VERSION 5.7 ;
  NOWIREEXTENSIONATPIN ON ;
  DIVIDERCHAR "/" ;
  BUSBITCHARS "[]" ;
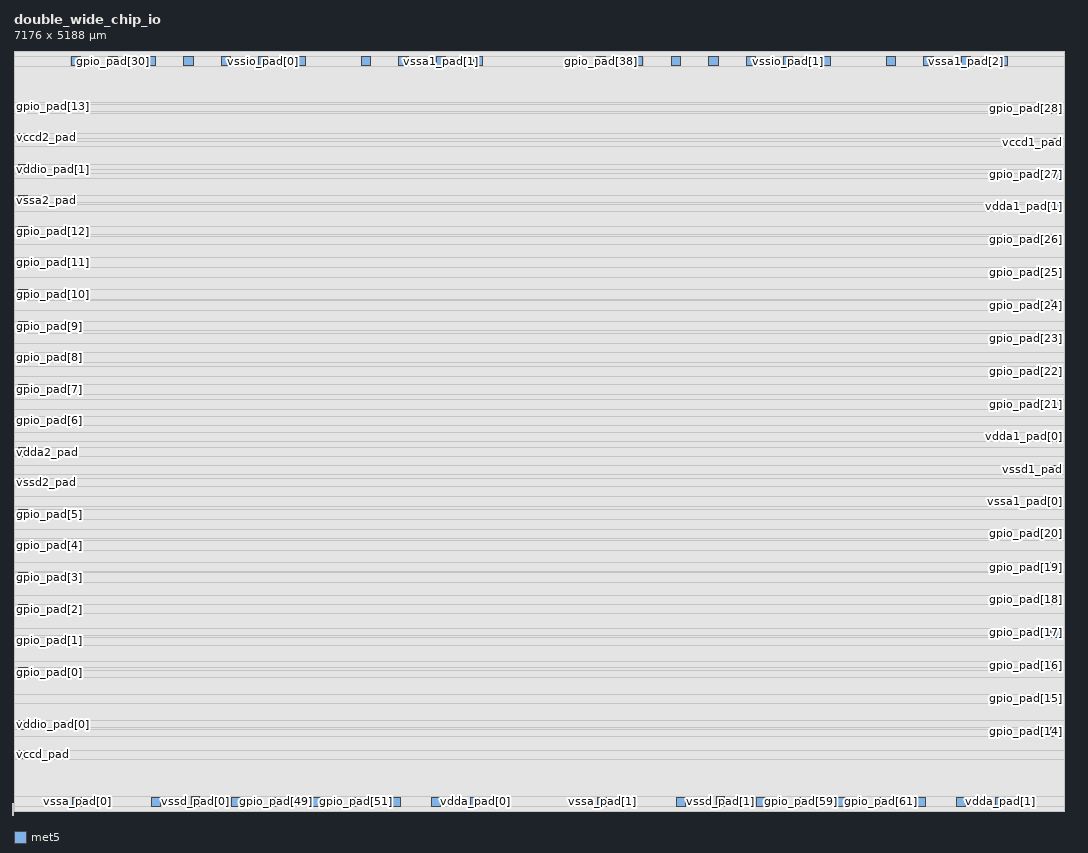
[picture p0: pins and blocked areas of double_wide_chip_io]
MACRO double_wide_chip_io
  CLASS BLOCK ;
  FOREIGN double_wide_chip_io ;
  ORIGIN 0.000 0.000 ;
  SIZE 7176.000 BY 5188.000 ;
  PIN gpio_pad[0]
    DIRECTION INOUT ;
    USE SIGNAL ;
    ANTENNADIFFAREA 426.799988 ;
    PORT
      LAYER met5 ;
        RECT 32.990 917.200 95.440 979.800 ;
    END
  END gpio_pad[0]
  PIN gpio_pad[10]
    DIRECTION INOUT ;
    USE SIGNAL ;
    ANTENNADIFFAREA 426.799988 ;
    PORT
      LAYER met5 ;
        RECT 32.990 3499.200 95.440 3561.800 ;
    END
  END gpio_pad[10]
  PIN gpio_pad[11]
    DIRECTION INOUT ;
    USE SIGNAL ;
    ANTENNADIFFAREA 426.799988 ;
    PORT
      LAYER met5 ;
        RECT 32.990 3715.200 95.440 3777.800 ;
    END
  END gpio_pad[11]
  PIN gpio_pad[12]
    DIRECTION INOUT ;
    USE SIGNAL ;
    ANTENNADIFFAREA 426.799988 ;
    PORT
      LAYER met5 ;
        RECT 32.990 3931.200 95.440 3993.800 ;
    END
  END gpio_pad[12]
  PIN gpio_pad[13]
    DIRECTION INOUT ;
    USE SIGNAL ;
    ANTENNADIFFAREA 426.799988 ;
    PORT
      LAYER met5 ;
        RECT 32.990 4780.200 95.440 4842.800 ;
    END
  END gpio_pad[13]
  PIN gpio_pad[14]
    DIRECTION INOUT ;
    USE SIGNAL ;
    ANTENNADIFFAREA 426.799988 ;
    PORT
      LAYER met5 ;
        RECT 7080.560 509.200 7143.010 571.800 ;
    END
  END gpio_pad[14]
  PIN gpio_pad[15]
    DIRECTION INOUT ;
    USE SIGNAL ;
    ANTENNADIFFAREA 426.799988 ;
    PORT
      LAYER met5 ;
        RECT 7080.560 735.200 7143.010 797.800 ;
    END
  END gpio_pad[15]
  PIN gpio_pad[16]
    DIRECTION INOUT ;
    USE SIGNAL ;
    ANTENNADIFFAREA 426.799988 ;
    PORT
      LAYER met5 ;
        RECT 7080.560 960.200 7143.010 1022.800 ;
    END
  END gpio_pad[16]
  PIN gpio_pad[17]
    DIRECTION INOUT ;
    USE SIGNAL ;
    ANTENNADIFFAREA 426.799988 ;
    PORT
      LAYER met5 ;
        RECT 7080.560 1186.200 7143.010 1248.800 ;
    END
  END gpio_pad[17]
  PIN gpio_pad[18]
    DIRECTION INOUT ;
    USE SIGNAL ;
    ANTENNADIFFAREA 426.799988 ;
    PORT
      LAYER met5 ;
        RECT 7080.560 1411.200 7143.010 1473.800 ;
    END
  END gpio_pad[18]
  PIN gpio_pad[19]
    DIRECTION INOUT ;
    USE SIGNAL ;
    ANTENNADIFFAREA 426.799988 ;
    PORT
      LAYER met5 ;
        RECT 7080.560 1636.200 7143.010 1698.800 ;
    END
  END gpio_pad[19]
  PIN gpio_pad[1]
    DIRECTION INOUT ;
    USE SIGNAL ;
    ANTENNADIFFAREA 426.799988 ;
    PORT
      LAYER met5 ;
        RECT 32.990 1133.200 95.440 1195.800 ;
    END
  END gpio_pad[1]
  PIN gpio_pad[20]
    DIRECTION INOUT ;
    USE SIGNAL ;
    ANTENNADIFFAREA 426.799988 ;
    PORT
      LAYER met5 ;
        RECT 7080.560 1862.200 7143.010 1924.800 ;
    END
  END gpio_pad[20]
  PIN gpio_pad[21]
    DIRECTION INOUT ;
    USE SIGNAL ;
    ANTENNADIFFAREA 426.799988 ;
    PORT
      LAYER met5 ;
        RECT 7080.560 2748.200 7143.010 2810.800 ;
    END
  END gpio_pad[21]
  PIN gpio_pad[22]
    DIRECTION INOUT ;
    USE SIGNAL ;
    ANTENNADIFFAREA 426.799988 ;
    PORT
      LAYER met5 ;
        RECT 7080.560 2974.200 7143.010 3036.800 ;
    END
  END gpio_pad[22]
  PIN gpio_pad[23]
    DIRECTION INOUT ;
    USE SIGNAL ;
    ANTENNADIFFAREA 426.799988 ;
    PORT
      LAYER met5 ;
        RECT 7080.560 3199.200 7143.010 3261.800 ;
    END
  END gpio_pad[23]
  PIN gpio_pad[24]
    DIRECTION INOUT ;
    USE SIGNAL ;
    ANTENNADIFFAREA 426.799988 ;
    PORT
      LAYER met5 ;
        RECT 7080.560 3425.200 7143.010 3487.800 ;
    END
  END gpio_pad[24]
  PIN gpio_pad[25]
    DIRECTION INOUT ;
    USE SIGNAL ;
    ANTENNADIFFAREA 426.799988 ;
    PORT
      LAYER met5 ;
        RECT 7080.560 3650.200 7143.010 3712.800 ;
    END
  END gpio_pad[25]
  PIN gpio_pad[26]
    DIRECTION INOUT ;
    USE SIGNAL ;
    ANTENNADIFFAREA 426.799988 ;
    PORT
      LAYER met5 ;
        RECT 7080.560 3875.200 7143.010 3937.800 ;
    END
  END gpio_pad[26]
  PIN gpio_pad[27]
    DIRECTION INOUT ;
    USE SIGNAL ;
    ANTENNADIFFAREA 426.799988 ;
    PORT
      LAYER met5 ;
        RECT 7080.560 4321.200 7143.010 4383.800 ;
    END
  END gpio_pad[27]
  PIN gpio_pad[28]
    DIRECTION INOUT ;
    USE SIGNAL ;
    ANTENNADIFFAREA 426.799988 ;
    PORT
      LAYER met5 ;
        RECT 7080.560 4767.200 7143.010 4829.800 ;
    END
  END gpio_pad[28]
  PIN gpio_pad[29]
    DIRECTION INOUT ;
    USE SIGNAL ;
    ANTENNADIFFAREA 426.799988 ;
    PORT
      LAYER met5 ;
        RECT 390.200 5092.560 452.800 5155.010 ;
    END
  END gpio_pad[29]
  PIN gpio_pad[2]
    DIRECTION INOUT ;
    USE SIGNAL ;
    ANTENNADIFFAREA 426.799988 ;
    PORT
      LAYER met5 ;
        RECT 32.990 1349.200 95.440 1411.800 ;
    END
  END gpio_pad[2]
  PIN gpio_pad[30]
    DIRECTION INOUT ;
    USE SIGNAL ;
    ANTENNADIFFAREA 426.799988 ;
    PORT
      LAYER met5 ;
        RECT 647.200 5092.560 709.800 5155.010 ;
    END
  END gpio_pad[30]
  PIN gpio_pad[31]
    DIRECTION INOUT ;
    USE SIGNAL ;
    ANTENNADIFFAREA 426.799988 ;
    PORT
      LAYER met5 ;
        RECT 904.200 5092.560 966.800 5155.010 ;
    END
  END gpio_pad[31]
  PIN gpio_pad[32]
    DIRECTION INOUT ;
    USE SIGNAL ;
    ANTENNADIFFAREA 426.799988 ;
    PORT
      LAYER met5 ;
        RECT 1161.200 5092.560 1223.800 5155.010 ;
    END
  END gpio_pad[32]
  PIN gpio_pad[33]
    DIRECTION INOUT ;
    USE SIGNAL ;
    ANTENNADIFFAREA 426.799988 ;
    PORT
      LAYER met5 ;
        RECT 1419.200 5092.560 1481.800 5155.010 ;
    END
  END gpio_pad[33]
  PIN gpio_pad[34]
    DIRECTION INOUT ;
    USE SIGNAL ;
    ANTENNADIFFAREA 426.799988 ;
    PORT
      LAYER met5 ;
        RECT 1928.200 5092.560 1990.800 5155.010 ;
    END
  END gpio_pad[34]
  PIN gpio_pad[35]
    DIRECTION INOUT ;
    USE SIGNAL ;
    ANTENNADIFFAREA 426.799988 ;
    PORT
      LAYER met5 ;
        RECT 2373.200 5092.560 2435.800 5155.010 ;
    END
  END gpio_pad[35]
  PIN gpio_pad[36]
    DIRECTION INOUT ;
    USE SIGNAL ;
    ANTENNADIFFAREA 426.799988 ;
    PORT
      LAYER met5 ;
        RECT 2630.200 5092.560 2692.800 5155.010 ;
    END
  END gpio_pad[36]
  PIN gpio_pad[37]
    DIRECTION INOUT ;
    USE SIGNAL ;
    ANTENNADIFFAREA 426.799988 ;
    PORT
      LAYER met5 ;
        RECT 3139.200 5092.560 3201.800 5155.010 ;
    END
  END gpio_pad[37]
  PIN gpio_pad[38]
    DIRECTION INOUT ;
    USE SIGNAL ;
    ANTENNADIFFAREA 426.799988 ;
    PORT
      LAYER met5 ;
        RECT 3978.200 5092.560 4040.800 5155.010 ;
    END
  END gpio_pad[38]
  PIN gpio_pad[39]
    DIRECTION INOUT ;
    USE SIGNAL ;
    ANTENNADIFFAREA 426.799988 ;
    PORT
      LAYER met5 ;
        RECT 4235.200 5092.560 4297.800 5155.010 ;
    END
  END gpio_pad[39]
  PIN gpio_pad[3]
    DIRECTION INOUT ;
    USE SIGNAL ;
    ANTENNADIFFAREA 426.799988 ;
    PORT
      LAYER met5 ;
        RECT 32.990 1565.200 95.440 1627.800 ;
    END
  END gpio_pad[3]
  PIN gpio_pad[40]
    DIRECTION INOUT ;
    USE SIGNAL ;
    ANTENNADIFFAREA 426.799988 ;
    PORT
      LAYER met5 ;
        RECT 4492.200 5092.560 4554.800 5155.010 ;
    END
  END gpio_pad[40]
  PIN gpio_pad[41]
    DIRECTION INOUT ;
    USE SIGNAL ;
    ANTENNADIFFAREA 426.799988 ;
    PORT
      LAYER met5 ;
        RECT 4749.200 5092.560 4811.800 5155.010 ;
    END
  END gpio_pad[41]
  PIN gpio_pad[42]
    DIRECTION INOUT ;
    USE SIGNAL ;
    ANTENNADIFFAREA 426.799988 ;
    PORT
      LAYER met5 ;
        RECT 5007.200 5092.560 5069.800 5155.010 ;
    END
  END gpio_pad[42]
  PIN gpio_pad[43]
    DIRECTION INOUT ;
    USE SIGNAL ;
    ANTENNADIFFAREA 426.799988 ;
    PORT
      LAYER met5 ;
        RECT 5516.200 5092.560 5578.800 5155.010 ;
    END
  END gpio_pad[43]
  PIN gpio_pad[44]
    DIRECTION INOUT ;
    USE SIGNAL ;
    ANTENNADIFFAREA 426.799988 ;
    PORT
      LAYER met5 ;
        RECT 5961.200 5092.560 6023.800 5155.010 ;
    END
  END gpio_pad[44]
  PIN gpio_pad[45]
    DIRECTION INOUT ;
    USE SIGNAL ;
    ANTENNADIFFAREA 426.799988 ;
    PORT
      LAYER met5 ;
        RECT 6218.200 5092.560 6280.800 5155.010 ;
    END
  END gpio_pad[45]
  PIN gpio_pad[46]
    DIRECTION INOUT ;
    USE SIGNAL ;
    ANTENNADIFFAREA 426.799988 ;
    PORT
      LAYER met5 ;
        RECT 6727.200 5092.560 6789.800 5155.010 ;
    END
  END gpio_pad[46]
  PIN gpio_pad[47]
    DIRECTION INOUT ;
    USE SIGNAL ;
    ANTENNADIFFAREA 426.799988 ;
    PORT
      LAYER met5 ;
        RECT 941.200 32.990 1003.800 95.440 ;
    END
  END gpio_pad[47]
  PIN gpio_pad[48]
    DIRECTION INOUT ;
    USE SIGNAL ;
    ANTENNADIFFAREA 426.799988 ;
    PORT
      LAYER met5 ;
        RECT 1484.200 32.990 1546.800 95.440 ;
    END
  END gpio_pad[48]
  PIN gpio_pad[49]
    DIRECTION INOUT ;
    USE SIGNAL ;
    ANTENNADIFFAREA 426.799988 ;
    PORT
      LAYER met5 ;
        RECT 1758.200 32.990 1820.800 95.440 ;
    END
  END gpio_pad[49]
  PIN gpio_pad[4]
    DIRECTION INOUT ;
    USE SIGNAL ;
    ANTENNADIFFAREA 426.799988 ;
    PORT
      LAYER met5 ;
        RECT 32.990 1781.200 95.440 1843.800 ;
    END
  END gpio_pad[4]
  PIN gpio_pad[50]
    DIRECTION INOUT ;
    USE SIGNAL ;
    ANTENNADIFFAREA 426.799988 ;
    PORT
      LAYER met5 ;
        RECT 2032.200 32.990 2094.800 95.440 ;
    END
  END gpio_pad[50]
  PIN gpio_pad[51]
    DIRECTION INOUT ;
    USE SIGNAL ;
    ANTENNADIFFAREA 426.799988 ;
    PORT
      LAYER met5 ;
        RECT 2306.200 32.990 2368.800 95.440 ;
    END
  END gpio_pad[51]
  PIN gpio_pad[52]
    DIRECTION INOUT ;
    USE SIGNAL ;
    ANTENNADIFFAREA 426.799988 ;
    PORT
      LAYER met5 ;
        RECT 2580.200 32.990 2642.800 95.440 ;
    END
  END gpio_pad[52]
  PIN gpio_pad[53]
    DIRECTION INOUT ;
    USE SIGNAL ;
    ANTENNADIFFAREA 426.799988 ;
    PORT
      LAYER met5 ;
        RECT 4529.200 32.990 4591.800 95.440 ;
    END
  END gpio_pad[53]
  PIN gpio_pad[54]
    DIRECTION INOUT ;
    USE SIGNAL ;
    ANTENNADIFFAREA 426.799988 ;
    PORT
      LAYER met5 ;
        RECT 5072.200 32.990 5134.800 95.440 ;
    END
  END gpio_pad[54]
  PIN gpio_pad[55]
    DIRECTION INOUT ;
    USE SIGNAL ;
    ANTENNADIFFAREA 426.799988 ;
    PORT
      LAYER met5 ;
        RECT 5346.200 32.990 5408.800 95.440 ;
    END
  END gpio_pad[55]
  PIN gpio_pad[56]
    DIRECTION INOUT ;
    USE SIGNAL ;
    ANTENNADIFFAREA 426.799988 ;
    PORT
      LAYER met5 ;
        RECT 5620.200 32.990 5682.800 95.440 ;
    END
  END gpio_pad[56]
  PIN gpio_pad[57]
    DIRECTION INOUT ;
    USE SIGNAL ;
    ANTENNADIFFAREA 426.799988 ;
    PORT
      LAYER met5 ;
        RECT 5894.200 32.990 5956.800 95.440 ;
    END
  END gpio_pad[57]
  PIN gpio_pad[58]
    DIRECTION INOUT ;
    USE SIGNAL ;
    ANTENNADIFFAREA 426.799988 ;
    PORT
      LAYER met5 ;
        RECT 6168.200 32.990 6230.800 95.440 ;
    END
  END gpio_pad[58]
  PIN gpio_pad[5]
    DIRECTION INOUT ;
    USE SIGNAL ;
    ANTENNADIFFAREA 426.799988 ;
    PORT
      LAYER met5 ;
        RECT 32.990 1997.200 95.440 2059.800 ;
    END
  END gpio_pad[5]
  PIN gpio_pad[6]
    DIRECTION INOUT ;
    USE SIGNAL ;
    ANTENNADIFFAREA 426.799988 ;
    PORT
      LAYER met5 ;
        RECT 32.990 2635.200 95.440 2697.800 ;
    END
  END gpio_pad[6]
  PIN gpio_pad[7]
    DIRECTION INOUT ;
    USE SIGNAL ;
    ANTENNADIFFAREA 426.799988 ;
    PORT
      LAYER met5 ;
        RECT 32.990 2851.200 95.440 2913.800 ;
    END
  END gpio_pad[7]
  PIN gpio_pad[8]
    DIRECTION INOUT ;
    USE SIGNAL ;
    ANTENNADIFFAREA 426.799988 ;
    PORT
      LAYER met5 ;
        RECT 32.990 3067.200 95.440 3129.800 ;
    END
  END gpio_pad[8]
  PIN gpio_pad[9]
    DIRECTION INOUT ;
    USE SIGNAL ;
    ANTENNADIFFAREA 426.799988 ;
    PORT
      LAYER met5 ;
        RECT 32.990 3283.200 95.440 3345.800 ;
    END
  END gpio_pad[9]
  PIN vccd1_pad
    DIRECTION INOUT ;
    USE POWER ;
    PORT
      LAYER met5 ;
        RECT 7077.900 4543.330 7145.165 4597.730 ;
    END
  END vccd1_pad
  PIN vccd2_pad
    DIRECTION INOUT ;
    USE POWER ;
    PORT
      LAYER met5 ;
        RECT 30.835 4575.330 98.100 4629.730 ;
    END
  END vccd2_pad
  PIN vccd_pad
    DIRECTION INOUT ;
    USE POWER ;
    PORT
      LAYER met5 ;
        RECT 30.835 356.330 98.100 410.730 ;
    END
  END vccd_pad
  PIN vdda1_pad[0]
    DIRECTION INOUT ;
    USE POWER ;
    PORT
      LAYER met5 ;
        RECT 7081.120 2526.110 7141.945 2586.950 ;
    END
  END vdda1_pad[0]
  PIN vdda1_pad[1]
    DIRECTION INOUT ;
    USE POWER ;
    PORT
      LAYER met5 ;
        RECT 7081.120 4099.110 7141.945 4159.950 ;
    END
  END vdda1_pad[1]
  PIN vdda2_pad
    DIRECTION INOUT ;
    USE POWER ;
    PORT
      LAYER met5 ;
        RECT 34.055 2422.110 94.880 2482.950 ;
    END
  END vdda2_pad
  PIN vdda_pad[0]
    DIRECTION INOUT ;
    USE POWER ;
    PORT
      LAYER met5 ;
        RECT 3121.110 34.055 3181.950 94.880 ;
    END
  END vdda_pad[0]
  PIN vdda_pad[1]
    DIRECTION INOUT ;
    USE POWER ;
    PORT
      LAYER met5 ;
        RECT 6709.110 34.055 6769.950 94.880 ;
    END
  END vdda_pad[1]
  PIN vddio_pad[0]
    DIRECTION INOUT ;
    USE POWER ;
    PORT
      LAYER met5 ;
        RECT 34.055 558.110 94.880 618.950 ;
    END
  END vddio_pad[0]
  PIN vddio_pad[1]
    DIRECTION INOUT ;
    USE POWER ;
    PORT
      LAYER met5 ;
        RECT 34.055 4356.110 94.880 4416.950 ;
    END
  END vddio_pad[1]
  PIN vssa1_pad[0]
    DIRECTION INOUT ;
    USE GROUND ;
    PORT
      LAYER met5 ;
        RECT 7081.120 2085.110 7141.945 2145.950 ;
    END
  END vssa1_pad[0]
  PIN vssa1_pad[1]
    DIRECTION INOUT ;
    USE GROUND ;
    PORT
      LAYER met5 ;
        RECT 2885.110 5093.120 2945.950 5153.945 ;
    END
  END vssa1_pad[1]
  PIN vssa1_pad[2]
    DIRECTION INOUT ;
    USE GROUND ;
    PORT
      LAYER met5 ;
        RECT 6473.110 5093.120 6533.950 5153.945 ;
    END
  END vssa1_pad[2]
  PIN vssa2_pad
    DIRECTION INOUT ;
    USE GROUND ;
    PORT
      LAYER met5 ;
        RECT 34.055 4145.110 94.880 4205.950 ;
    END
  END vssa2_pad
  PIN vssa_pad[0]
    DIRECTION INOUT ;
    USE GROUND ;
    PORT
      LAYER met5 ;
        RECT 401.110 34.055 461.950 94.880 ;
    END
  END vssa_pad[0]
  PIN vssa_pad[1]
    DIRECTION INOUT ;
    USE GROUND ;
    PORT
      LAYER met5 ;
        RECT 3989.110 34.055 4049.950 94.880 ;
    END
  END vssa_pad[1]
  PIN vssd1_pad
    DIRECTION INOUT ;
    USE GROUND ;
    PORT
      LAYER met5 ;
        RECT 7077.900 2304.330 7145.165 2358.730 ;
    END
  END vssd1_pad
  PIN vssd2_pad
    DIRECTION INOUT ;
    USE GROUND ;
    PORT
      LAYER met5 ;
        RECT 30.835 2219.330 98.100 2273.730 ;
    END
  END vssd2_pad
  PIN vssd_pad[0]
    DIRECTION INOUT ;
    USE GROUND ;
    PORT
      LAYER met5 ;
        RECT 1210.330 30.835 1264.730 98.100 ;
    END
  END vssd_pad[0]
  PIN vssd_pad[1]
    DIRECTION INOUT ;
    USE GROUND ;
    PORT
      LAYER met5 ;
        RECT 4798.330 30.835 4852.730 98.100 ;
    END
  END vssd_pad[1]
  PIN vssio_pad[0]
    DIRECTION INOUT ;
    USE GROUND ;
    PORT
      LAYER met5 ;
        RECT 1674.110 5093.120 1734.950 5153.945 ;
    END
  END vssio_pad[0]
  PIN vssio_pad[1]
    DIRECTION INOUT ;
    USE GROUND ;
    PORT
      LAYER met5 ;
        RECT 5262.110 5093.120 5322.950 5153.945 ;
    END
  END vssio_pad[1]
  PIN vssio_pad[2]
    DIRECTION INOUT ;
    USE GROUND ;
    PORT
      LAYER met5 ;
        RECT 2852.110 34.055 2912.950 94.880 ;
    END
  END vssio_pad[2]
  PIN vssio_pad[3]
    DIRECTION INOUT ;
    USE GROUND ;
    PORT
      LAYER met5 ;
        RECT 6440.110 34.055 6500.950 94.880 ;
    END
  END vssio_pad[3]
  PIN gpio_pad[59]
    DIRECTION INOUT ;
    USE SIGNAL ;
    PORT
      LAYER met5 ;
        RECT 5346.275 32.990 5408.725 95.440 ;
    END
  END gpio_pad[59]
  PIN gpio_pad[60]
    DIRECTION INOUT ;
    USE SIGNAL ;
    PORT
      LAYER met5 ;
        RECT 5620.275 32.990 5682.725 95.440 ;
    END
  END gpio_pad[60]
  PIN gpio_pad[61]
    DIRECTION INOUT ;
    USE SIGNAL ;
    PORT
      LAYER met5 ;
        RECT 5894.275 32.990 5956.725 95.440 ;
    END
  END gpio_pad[61]
  PIN gpio_pad[62]
    DIRECTION INOUT ;
    USE SIGNAL ;
    PORT
      LAYER met5 ;
        RECT 6168.275 32.990 6230.725 95.440 ;
    END
  END gpio_pad[62]
  OBS
      LAYER nwell ;
        RECT 0.000 0.000 7176.000 5188.000 ;
      LAYER li1 ;
        RECT 0.000 43.380 7176.000 5188.000 ;
        RECT -0.070 42.760 7176.000 43.380 ;
        RECT 0.000 0.000 7176.000 42.760 ;
      LAYER met1 ;
        RECT 0.000 43.420 7176.000 5188.000 ;
        RECT -0.070 42.720 7176.000 43.420 ;
        RECT 0.000 0.000 7176.000 42.720 ;
      LAYER met2 ;
        RECT 0.000 43.420 7176.000 5188.000 ;
        RECT -0.070 42.720 7176.000 43.420 ;
        RECT 0.000 0.000 7176.000 42.720 ;
      LAYER met3 ;
        RECT 0.000 43.420 7176.000 5188.000 ;
        RECT -0.070 42.190 7176.000 43.420 ;
        RECT 0.000 0.000 7176.000 42.190 ;
      LAYER met4 ;
        RECT -7.045 41.415 -2.155 51.320 ;
        RECT 0.000 41.415 7176.000 5188.000 ;
        RECT -7.045 39.825 7176.000 41.415 ;
        RECT 0.000 38.275 7176.000 39.825 ;
        RECT -7.040 36.275 7176.000 38.275 ;
        RECT -7.040 -32.540 -2.060 36.275 ;
        RECT 0.000 0.000 7176.000 36.275 ;
      LAYER met5 ;
        RECT 0.000 5156.610 7176.000 5188.000 ;
        RECT 0.000 5090.960 388.600 5156.610 ;
        RECT 454.400 5090.960 645.600 5156.610 ;
        RECT 711.400 5090.960 902.600 5156.610 ;
        RECT 968.400 5090.960 1159.600 5156.610 ;
        RECT 1225.400 5090.960 1417.600 5156.610 ;
        RECT 1483.400 5155.545 1926.600 5156.610 ;
        RECT 1483.400 5091.520 1672.510 5155.545 ;
        RECT 1736.550 5091.520 1926.600 5155.545 ;
        RECT 1483.400 5090.960 1926.600 5091.520 ;
        RECT 1992.400 5090.960 2371.600 5156.610 ;
        RECT 2437.400 5090.960 2628.600 5156.610 ;
        RECT 2694.400 5155.545 3137.600 5156.610 ;
        RECT 2694.400 5091.520 2883.510 5155.545 ;
        RECT 2947.550 5091.520 3137.600 5155.545 ;
        RECT 2694.400 5090.960 3137.600 5091.520 ;
        RECT 3203.400 5090.960 3976.600 5156.610 ;
        RECT 4042.400 5090.960 4233.600 5156.610 ;
        RECT 4299.400 5090.960 4490.600 5156.610 ;
        RECT 4556.400 5090.960 4747.600 5156.610 ;
        RECT 4813.400 5090.960 5005.600 5156.610 ;
        RECT 5071.400 5155.545 5514.600 5156.610 ;
        RECT 5071.400 5091.520 5260.510 5155.545 ;
        RECT 5324.550 5091.520 5514.600 5155.545 ;
        RECT 5071.400 5090.960 5514.600 5091.520 ;
        RECT 5580.400 5090.960 5959.600 5156.610 ;
        RECT 6025.400 5090.960 6216.600 5156.610 ;
        RECT 6282.400 5155.545 6725.600 5156.610 ;
        RECT 6282.400 5091.520 6471.510 5155.545 ;
        RECT 6535.550 5091.520 6725.600 5155.545 ;
        RECT 6282.400 5090.960 6725.600 5091.520 ;
        RECT 6791.400 5090.960 7176.000 5156.610 ;
        RECT 0.000 4844.400 7176.000 5090.960 ;
        RECT 0.000 4778.600 31.390 4844.400 ;
        RECT 97.040 4831.400 7176.000 4844.400 ;
        RECT 97.040 4778.600 7078.960 4831.400 ;
        RECT 0.000 4765.600 7078.960 4778.600 ;
        RECT 7144.610 4765.600 7176.000 4831.400 ;
        RECT 0.000 4631.330 7176.000 4765.600 ;
        RECT 0.000 4573.730 29.235 4631.330 ;
        RECT 99.700 4599.330 7176.000 4631.330 ;
        RECT 99.700 4573.730 7076.300 4599.330 ;
        RECT 0.000 4541.730 7076.300 4573.730 ;
        RECT 7146.765 4541.730 7176.000 4599.330 ;
        RECT 0.000 4418.550 7176.000 4541.730 ;
        RECT 0.000 4354.510 32.455 4418.550 ;
        RECT 96.480 4385.400 7176.000 4418.550 ;
        RECT 96.480 4354.510 7078.960 4385.400 ;
        RECT 0.000 4319.600 7078.960 4354.510 ;
        RECT 7144.610 4319.600 7176.000 4385.400 ;
        RECT 0.000 4207.550 7176.000 4319.600 ;
        RECT 0.000 4143.510 32.455 4207.550 ;
        RECT 96.480 4161.550 7176.000 4207.550 ;
        RECT 96.480 4143.510 7079.520 4161.550 ;
        RECT 0.000 4097.510 7079.520 4143.510 ;
        RECT 7143.545 4097.510 7176.000 4161.550 ;
        RECT 0.000 3995.400 7176.000 4097.510 ;
        RECT 0.000 3929.600 31.390 3995.400 ;
        RECT 97.040 3939.400 7176.000 3995.400 ;
        RECT 97.040 3929.600 7078.960 3939.400 ;
        RECT 0.000 3873.600 7078.960 3929.600 ;
        RECT 7144.610 3873.600 7176.000 3939.400 ;
        RECT 0.000 3779.400 7176.000 3873.600 ;
        RECT 0.000 3713.600 31.390 3779.400 ;
        RECT 97.040 3714.400 7176.000 3779.400 ;
        RECT 97.040 3713.600 7078.960 3714.400 ;
        RECT 0.000 3648.600 7078.960 3713.600 ;
        RECT 7144.610 3648.600 7176.000 3714.400 ;
        RECT 0.000 3563.400 7176.000 3648.600 ;
        RECT 0.000 3497.600 31.390 3563.400 ;
        RECT 97.040 3497.600 7176.000 3563.400 ;
        RECT 0.000 3489.400 7176.000 3497.600 ;
        RECT 0.000 3423.600 7078.960 3489.400 ;
        RECT 7144.610 3423.600 7176.000 3489.400 ;
        RECT 0.000 3347.400 7176.000 3423.600 ;
        RECT 0.000 3281.600 31.390 3347.400 ;
        RECT 97.040 3281.600 7176.000 3347.400 ;
        RECT 0.000 3263.400 7176.000 3281.600 ;
        RECT 0.000 3197.600 7078.960 3263.400 ;
        RECT 7144.610 3197.600 7176.000 3263.400 ;
        RECT 0.000 3131.400 7176.000 3197.600 ;
        RECT 0.000 3065.600 31.390 3131.400 ;
        RECT 97.040 3065.600 7176.000 3131.400 ;
        RECT 0.000 3038.400 7176.000 3065.600 ;
        RECT 0.000 2972.600 7078.960 3038.400 ;
        RECT 7144.610 2972.600 7176.000 3038.400 ;
        RECT 0.000 2915.400 7176.000 2972.600 ;
        RECT 0.000 2849.600 31.390 2915.400 ;
        RECT 97.040 2849.600 7176.000 2915.400 ;
        RECT 0.000 2812.400 7176.000 2849.600 ;
        RECT 0.000 2746.600 7078.960 2812.400 ;
        RECT 7144.610 2746.600 7176.000 2812.400 ;
        RECT 0.000 2699.400 7176.000 2746.600 ;
        RECT 0.000 2633.600 31.390 2699.400 ;
        RECT 97.040 2633.600 7176.000 2699.400 ;
        RECT 0.000 2588.550 7176.000 2633.600 ;
        RECT 0.000 2524.510 7079.520 2588.550 ;
        RECT 7143.545 2524.510 7176.000 2588.550 ;
        RECT 0.000 2484.550 7176.000 2524.510 ;
        RECT 0.000 2420.510 32.455 2484.550 ;
        RECT 96.480 2420.510 7176.000 2484.550 ;
        RECT 0.000 2360.330 7176.000 2420.510 ;
        RECT 0.000 2302.730 7076.300 2360.330 ;
        RECT 7146.765 2302.730 7176.000 2360.330 ;
        RECT 0.000 2275.330 7176.000 2302.730 ;
        RECT 0.000 2217.730 29.235 2275.330 ;
        RECT 99.700 2217.730 7176.000 2275.330 ;
        RECT 0.000 2147.550 7176.000 2217.730 ;
        RECT 0.000 2083.510 7079.520 2147.550 ;
        RECT 7143.545 2083.510 7176.000 2147.550 ;
        RECT 0.000 2061.400 7176.000 2083.510 ;
        RECT 0.000 1995.600 31.390 2061.400 ;
        RECT 97.040 1995.600 7176.000 2061.400 ;
        RECT 0.000 1926.400 7176.000 1995.600 ;
        RECT 0.000 1860.600 7078.960 1926.400 ;
        RECT 7144.610 1860.600 7176.000 1926.400 ;
        RECT 0.000 1845.400 7176.000 1860.600 ;
        RECT 0.000 1779.600 31.390 1845.400 ;
        RECT 97.040 1779.600 7176.000 1845.400 ;
        RECT 0.000 1700.400 7176.000 1779.600 ;
        RECT 0.000 1634.600 7078.960 1700.400 ;
        RECT 7144.610 1634.600 7176.000 1700.400 ;
        RECT 0.000 1629.400 7176.000 1634.600 ;
        RECT 0.000 1563.600 31.390 1629.400 ;
        RECT 97.040 1563.600 7176.000 1629.400 ;
        RECT 0.000 1475.400 7176.000 1563.600 ;
        RECT 0.000 1413.400 7078.960 1475.400 ;
        RECT 0.000 1347.600 31.390 1413.400 ;
        RECT 97.040 1409.600 7078.960 1413.400 ;
        RECT 7144.610 1409.600 7176.000 1475.400 ;
        RECT 97.040 1347.600 7176.000 1409.600 ;
        RECT 0.000 1250.400 7176.000 1347.600 ;
        RECT 0.000 1197.400 7078.960 1250.400 ;
        RECT 0.000 1131.600 31.390 1197.400 ;
        RECT 97.040 1184.600 7078.960 1197.400 ;
        RECT 7144.610 1184.600 7176.000 1250.400 ;
        RECT 97.040 1131.600 7176.000 1184.600 ;
        RECT 0.000 1024.400 7176.000 1131.600 ;
        RECT 0.000 981.400 7078.960 1024.400 ;
        RECT 0.000 915.600 31.390 981.400 ;
        RECT 97.040 958.600 7078.960 981.400 ;
        RECT 7144.610 958.600 7176.000 1024.400 ;
        RECT 97.040 915.600 7176.000 958.600 ;
        RECT 0.000 799.400 7176.000 915.600 ;
        RECT 0.000 733.600 7078.960 799.400 ;
        RECT 7144.610 733.600 7176.000 799.400 ;
        RECT 0.000 620.550 7176.000 733.600 ;
        RECT 0.000 556.510 32.455 620.550 ;
        RECT 96.480 573.400 7176.000 620.550 ;
        RECT 96.480 556.510 7078.960 573.400 ;
        RECT 0.000 507.600 7078.960 556.510 ;
        RECT 7144.610 507.600 7176.000 573.400 ;
        RECT 0.000 412.330 7176.000 507.600 ;
        RECT 0.000 354.730 29.235 412.330 ;
        RECT 99.700 354.730 7176.000 412.330 ;
        RECT 0.000 99.700 7176.000 354.730 ;
        RECT 0.000 97.040 1208.730 99.700 ;
        RECT 0.000 96.480 939.600 97.040 ;
        RECT 0.000 32.455 399.510 96.480 ;
        RECT 463.550 32.455 939.600 96.480 ;
        RECT 0.000 31.390 939.600 32.455 ;
        RECT 1005.400 31.390 1208.730 97.040 ;
        RECT 0.000 29.235 1208.730 31.390 ;
        RECT 1266.330 97.040 4796.730 99.700 ;
        RECT 1266.330 31.390 1482.600 97.040 ;
        RECT 1548.400 31.390 1756.600 97.040 ;
        RECT 1822.400 31.390 2030.600 97.040 ;
        RECT 2096.400 31.390 2304.600 97.040 ;
        RECT 2370.400 31.390 2578.600 97.040 ;
        RECT 2644.400 96.480 4527.600 97.040 ;
        RECT 2644.400 32.455 2850.510 96.480 ;
        RECT 2914.550 32.455 3119.510 96.480 ;
        RECT 3183.550 32.455 3987.510 96.480 ;
        RECT 4051.550 32.455 4527.600 96.480 ;
        RECT 2644.400 31.390 4527.600 32.455 ;
        RECT 4593.400 31.390 4796.730 97.040 ;
        RECT 1266.330 29.235 4796.730 31.390 ;
        RECT 4854.330 97.040 7176.000 99.700 ;
        RECT 4854.330 31.390 5070.600 97.040 ;
        RECT 5136.400 31.390 5344.600 97.040 ;
        RECT 5410.400 31.390 5618.600 97.040 ;
        RECT 5684.400 31.390 5892.600 97.040 ;
        RECT 5958.400 31.390 6166.600 97.040 ;
        RECT 6232.400 96.480 7176.000 97.040 ;
        RECT 6232.400 32.455 6438.510 96.480 ;
        RECT 6502.550 32.455 6707.510 96.480 ;
        RECT 6771.550 32.455 7176.000 96.480 ;
        RECT 6232.400 31.390 7176.000 32.455 ;
        RECT 4854.330 29.235 7176.000 31.390 ;
        RECT 0.000 0.000 7176.000 29.235 ;
  END
END double_wide_chip_io
END LIBRARY

